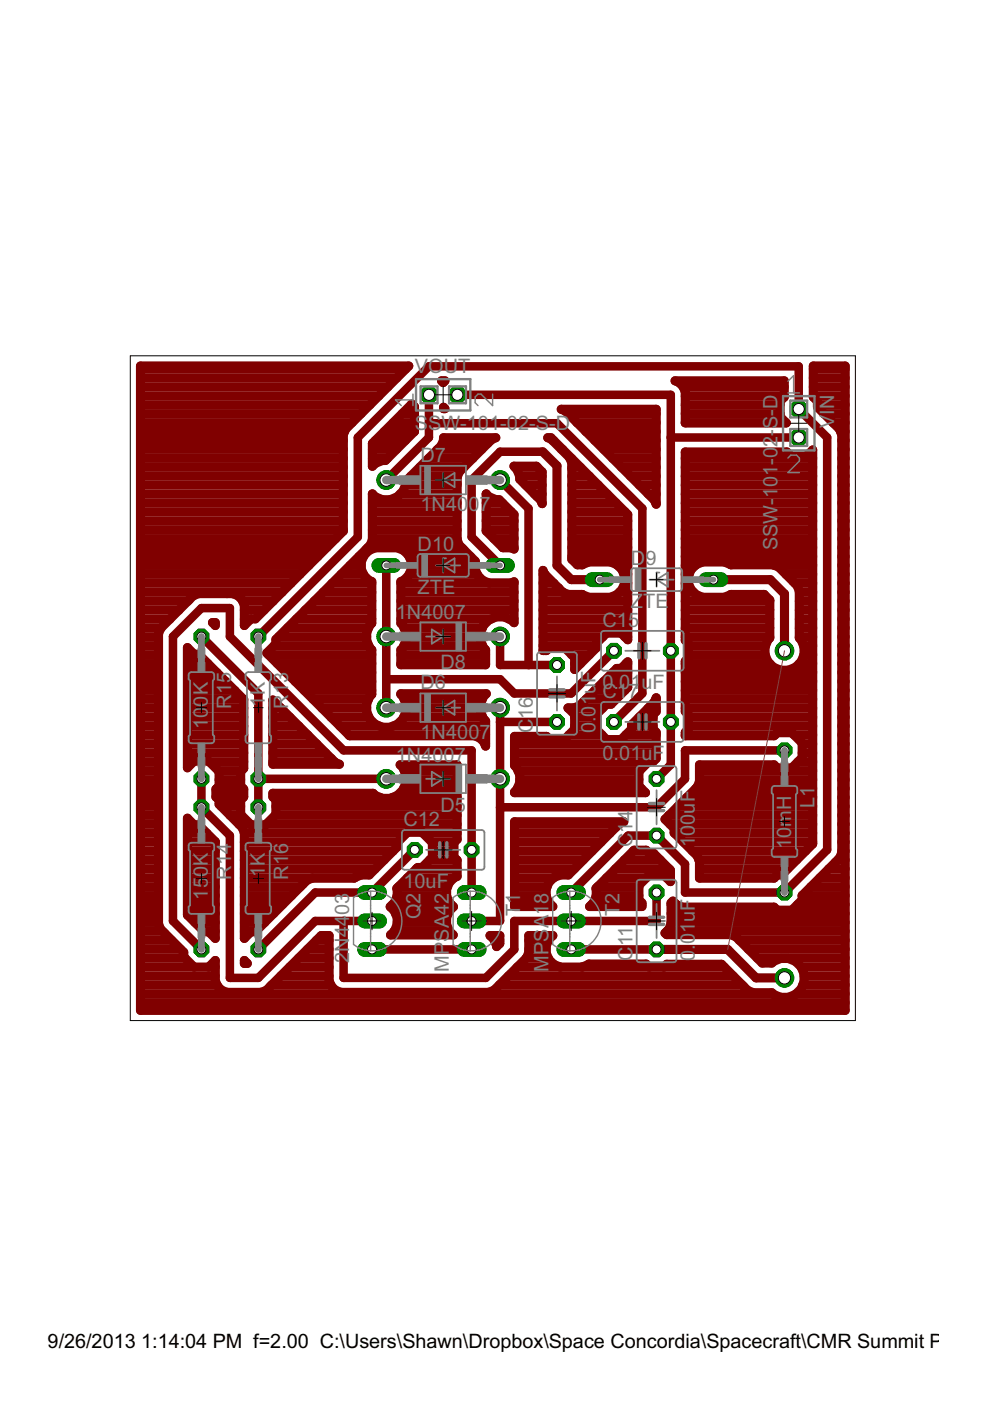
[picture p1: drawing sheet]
<svg xmlns="http://www.w3.org/2000/svg" width="176mm" height="250mm" viewBox="0 0 176 250" stroke-linecap="round" stroke-linejoin="round" font-family="sans-serif">
<defs><g id="words">
<g font-size="4" fill="#808080">
<text x="74" y="66.7">VOUT</text>
<text x="74" y="76.8">SSW-101-02-S-D</text>
<text x="138.8" y="77.8" transform="rotate(-90 138.8 77.8)">-S</text>
<text x="138.8" y="74.2" transform="rotate(-90 138.8 74.2)">-</text>
<text x="138.8" y="73.1" transform="rotate(-90 138.8 73.1)">D</text>
<text x="149" y="76.4" transform="rotate(-90 149 76.4)">VI</text>
<text x="149" y="73.1" transform="rotate(-90 149 73.1)">N</text>
<text x="75.1" y="82.4">D7</text>
<text x="138.8" y="83" transform="rotate(-90 138.8 83)">-</text>
<text x="138.8" y="81.8" transform="rotate(-90 138.8 81.8)">0</text>
<text x="138.8" y="79.8" transform="rotate(-90 138.8 79.8)">2</text>
<text x="138.8" y="89" transform="rotate(-90 138.8 89)">10</text>
<text x="138.8" y="85" transform="rotate(-90 138.8 85)">1</text>
<text x="75.1" y="91.3">1N4</text>
<text x="81.6" y="91.3">007</text>
<text x="138.8" y="95.9" transform="rotate(-90 138.8 95.9)">S</text>
<text x="138.8" y="93.5" transform="rotate(-90 138.8 93.5)">W-</text>
<text x="74.6" y="98.4">D10</text>
<text x="112.6" y="100.9">D</text>
<text x="115.2" y="100.9">9</text>
<text x="138.8" y="98.2" transform="rotate(-90 138.8 98.2)">S</text>
<text x="74.6" y="106">ZTE</text>
<text x="70.7" y="110.6">1</text>
<text x="72.6" y="110.6">N4007</text>
<text x="107.6" y="111.9">C1</text>
<text x="112.1" y="111.9">5</text>
<text x="112.6" y="108.6">Z</text>
<text x="114.8" y="108.6">TE</text>
<text x="78.6" y="119.5">D8</text>
<text x="37.1" y="124.2" transform="rotate(-90 37.1 124.2)">K</text>
<text x="41.3" y="124" transform="rotate(-90 41.3 124)">15</text>
<text x="75.1" y="123">D6</text>
<text x="106.3" y="125.9" transform="rotate(-90 106.3 125.9)">1</text>
<text x="106.3" y="123.9" transform="rotate(-90 106.3 123.9)">uF</text>
<text x="107.6" y="124.6">C17</text>
<text x="107.6" y="123">0.01uF</text>
<text x="37.1" y="130.1" transform="rotate(-90 37.1 130.1)">10</text>
<text x="37.1" y="126.2" transform="rotate(-90 37.1 126.2)">0</text>
<text x="41.3" y="126.6" transform="rotate(-90 41.3 126.6)">R</text>
<text x="47.3" y="126.2" transform="rotate(-90 47.3 126.2)">1K</text>
<text x="51.4" y="126.6" transform="rotate(-90 51.4 126.6)">R13</text>
<text x="75.1" y="131.9">1N4007</text>
<text x="95.1" y="130.9" transform="rotate(-90 95.1 130.9)">C</text>
<text x="95.1" y="128.3" transform="rotate(-90 95.1 128.3)">16</text>
<text x="106.3" y="130.9" transform="rotate(-90 106.3 130.9)">0</text>
<text x="106.3" y="128.9" transform="rotate(-90 106.3 128.9)">.</text>
<text x="106.3" y="127.9" transform="rotate(-90 106.3 127.9)">0</text>
<text x="70.7" y="136">1N4007</text>
<text x="107.6" y="135.7">0.01uF</text>
<text x="124.1" y="143.3" transform="rotate(-90 124.1 143.3)">F</text>
<text x="72" y="147.4">C12</text>
<text x="78.6" y="144.9">D5</text>
<text x="112.9" y="148.6" transform="rotate(-90 112.9 148.6)">14</text>
<text x="124.1" y="149.2" transform="rotate(-90 124.1 149.2)">00</text>
<text x="124.1" y="145.3" transform="rotate(-90 124.1 145.3)">u</text>
<text x="141.2" y="149.6" transform="rotate(-90 141.2 149.6)">0</text>
<text x="141.2" y="147.7" transform="rotate(-90 141.2 147.7)">m</text>
<text x="141.2" y="144.7" transform="rotate(-90 141.2 144.7)">H</text>
<text x="145.4" y="144.3" transform="rotate(-90 145.4 144.3)">L1</text>
<text x="37.1" y="154.6" transform="rotate(-90 37.1 154.6)">K</text>
<text x="47.3" y="154.6" transform="rotate(-90 47.3 154.6)">K</text>
<text x="51.4" y="154.4" transform="rotate(-90 51.4 154.4)">1</text>
<text x="51.4" y="152.5" transform="rotate(-90 51.4 152.5)">6</text>
<text x="112.9" y="151.2" transform="rotate(-90 112.9 151.2)">C</text>
<text x="124.1" y="151.2" transform="rotate(-90 124.1 151.2)">1</text>
<text x="141.2" y="151.6" transform="rotate(-90 141.2 151.6)">1</text>
<text x="37.1" y="160.6" transform="rotate(-90 37.1 160.6)">15</text>
<text x="37.1" y="156.6" transform="rotate(-90 37.1 156.6)">0</text>
<text x="41.3" y="157" transform="rotate(-90 41.3 157)">R14</text>
<text x="47.3" y="156.6" transform="rotate(-90 47.3 156.6)">1</text>
<text x="51.4" y="157" transform="rotate(-90 51.4 157)">R</text>
<text x="72" y="158.6">10uF</text>
<text x="75.1" y="161.3" transform="rotate(-90 75.1 161.3)">2</text>
<text x="80.1" y="161.3" transform="rotate(-90 80.1 161.3)">2</text>
<text x="92.8" y="161.3" transform="rotate(-90 92.8 161.3)">1</text>
<text x="97.9" y="161.3" transform="rotate(-90 97.9 161.3)">8</text>
<text x="110.6" y="161.3" transform="rotate(-90 110.6 161.3)">2</text>
<text x="62.4" y="163.3" transform="rotate(-90 62.4 163.3)">03</text>
<text x="75.1" y="164.1" transform="rotate(-90 75.1 164.1)">Q</text>
<text x="80.1" y="165.7" transform="rotate(-90 80.1 165.7)">A4</text>
<text x="92.8" y="163.5" transform="rotate(-90 92.8 163.5)">T</text>
<text x="97.9" y="163.3" transform="rotate(-90 97.9 163.3)">1</text>
<text x="110.6" y="163.5" transform="rotate(-90 110.6 163.5)">T</text>
<text x="124.1" y="166.6" transform="rotate(-90 124.1 166.6)">1</text>
<text x="124.1" y="164.6" transform="rotate(-90 124.1 164.6)">u</text>
<text x="124.1" y="162.6" transform="rotate(-90 124.1 162.6)">F</text>
<text x="62.4" y="171.9" transform="rotate(-90 62.4 171.9)">2N44</text>
<text x="80.1" y="173.5" transform="rotate(-90 80.1 173.5)">MPS</text>
<text x="97.9" y="173.5" transform="rotate(-90 97.9 173.5)">MPSA</text>
<text x="112.9" y="171.5" transform="rotate(-90 112.9 171.5)">C</text>
<text x="112.9" y="169" transform="rotate(-90 112.9 169)">11</text>
<text x="124.1" y="171.5" transform="rotate(-90 124.1 171.5)">0.</text>
<text x="124.1" y="168.6" transform="rotate(-90 124.1 168.6)">0</text>
</g>
<g font-size="4">
<text x="8.5" y="240.6">9/26/2013</text>
<text x="25.2" y="240.6">1:14:04 PM f=2.00 C:\Users\Shawn\Dropbox\Space Concordia\Spacecraft\CMR Summit PCB M</text>
</g>
</g></defs>
<circle cx="46.1" cy="113.6" r="1.42" fill="#008000" stroke="#008000" stroke-width=".18"/>
<circle cx="46.1" cy="113.6" r=".8" fill="#fff" stroke="#000" stroke-width=".18"/>
<circle cx="46.1" cy="139" r="1.42" fill="#008000" stroke="#008000" stroke-width=".18"/>
<circle cx="46.1" cy="139" r=".8" fill="#fff" stroke="#000" stroke-width=".18"/>
<circle cx="36" cy="144.1" r="1.42" fill="#008000" stroke="#008000" stroke-width=".18"/>
<circle cx="36" cy="144.1" r=".8" fill="#fff" stroke="#000" stroke-width=".18"/>
<circle cx="36" cy="169.5" r="1.42" fill="#008000" stroke="#008000" stroke-width=".18"/>
<circle cx="36" cy="169.5" r=".8" fill="#fff" stroke="#000" stroke-width=".18"/>
<circle cx="36" cy="113.6" r="1.42" fill="#008000" stroke="#008000" stroke-width=".18"/>
<circle cx="36" cy="113.6" r=".8" fill="#fff" stroke="#000" stroke-width=".18"/>
<circle cx="36" cy="139" r="1.42" fill="#008000" stroke="#008000" stroke-width=".18"/>
<circle cx="36" cy="139" r=".8" fill="#fff" stroke="#000" stroke-width=".18"/>
<circle cx="46.1" cy="144.1" r="1.42" fill="#008000" stroke="#008000" stroke-width=".18"/>
<circle cx="46.1" cy="144.1" r=".8" fill="#fff" stroke="#000" stroke-width=".18"/>
<circle cx="46.1" cy="169.5" r="1.42" fill="#008000" stroke="#008000" stroke-width=".18"/>
<circle cx="46.1" cy="169.5" r=".8" fill="#fff" stroke="#000" stroke-width=".18"/>
<circle cx="117.2" cy="169.5" r="1.42" fill="#008000" stroke="#008000" stroke-width=".18"/>
<circle cx="117.2" cy="169.5" r=".8" fill="#fff" stroke="#000" stroke-width=".18"/>
<circle cx="117.2" cy="159.3" r="1.42" fill="#008000" stroke="#008000" stroke-width=".18"/>
<circle cx="117.2" cy="159.3" r=".8" fill="#fff" stroke="#000" stroke-width=".18"/>
<circle cx="74" cy="151.7" r="1.42" fill="#008000" stroke="#008000" stroke-width=".18"/>
<circle cx="74" cy="151.7" r=".8" fill="#fff" stroke="#000" stroke-width=".18"/>
<circle cx="84.2" cy="151.7" r="1.42" fill="#008000" stroke="#008000" stroke-width=".18"/>
<circle cx="84.2" cy="151.7" r=".8" fill="#fff" stroke="#000" stroke-width=".18"/>
<circle cx="117.2" cy="149.2" r="1.42" fill="#008000" stroke="#008000" stroke-width=".18"/>
<circle cx="117.2" cy="149.2" r=".8" fill="#fff" stroke="#000" stroke-width=".18"/>
<circle cx="117.2" cy="139" r="1.42" fill="#008000" stroke="#008000" stroke-width=".18"/>
<circle cx="117.2" cy="139" r=".8" fill="#fff" stroke="#000" stroke-width=".18"/>
<circle cx="109.6" cy="116.2" r="1.42" fill="#008000" stroke="#008000" stroke-width=".18"/>
<circle cx="109.6" cy="116.2" r=".8" fill="#fff" stroke="#000" stroke-width=".18"/>
<circle cx="119.8" cy="116.2" r="1.42" fill="#008000" stroke="#008000" stroke-width=".18"/>
<circle cx="119.8" cy="116.2" r=".8" fill="#fff" stroke="#000" stroke-width=".18"/>
<circle cx="99.4" cy="128.9" r="1.42" fill="#008000" stroke="#008000" stroke-width=".18"/>
<circle cx="99.4" cy="128.9" r=".8" fill="#fff" stroke="#000" stroke-width=".18"/>
<circle cx="99.4" cy="118.7" r="1.42" fill="#008000" stroke="#008000" stroke-width=".18"/>
<circle cx="99.4" cy="118.7" r=".8" fill="#fff" stroke="#000" stroke-width=".18"/>
<circle cx="109.6" cy="128.9" r="1.42" fill="#008000" stroke="#008000" stroke-width=".18"/>
<circle cx="109.6" cy="128.9" r=".8" fill="#fff" stroke="#000" stroke-width=".18"/>
<circle cx="119.8" cy="128.9" r="1.42" fill="#008000" stroke="#008000" stroke-width=".18"/>
<circle cx="119.8" cy="128.9" r=".8" fill="#fff" stroke="#000" stroke-width=".18"/>
<path d="M65.1 169.5h2.7" fill="none" stroke="#008000" stroke-width="2.6"/>
<circle cx="66.4" cy="169.5" r=".8" fill="#fff" stroke="#000" stroke-width=".18"/>
<path d="M65.1 159.3h2.7" fill="none" stroke="#008000" stroke-width="2.6"/>
<circle cx="66.4" cy="159.3" r=".8" fill="#fff" stroke="#000" stroke-width=".18"/>
<path d="M65.1 164.4h2.7" fill="none" stroke="#008000" stroke-width="2.6"/>
<circle cx="66.4" cy="164.4" r=".8" fill="#fff" stroke="#000" stroke-width=".18"/>
<circle cx="69" cy="139" r="1.67" fill="#008000" stroke="#008000" stroke-width=".18"/>
<circle cx="69" cy="139" r="1.12" fill="#fff" stroke="#000" stroke-width=".18"/>
<circle cx="89.3" cy="139" r="1.67" fill="#008000" stroke="#008000" stroke-width=".18"/>
<circle cx="89.3" cy="139" r="1.12" fill="#fff" stroke="#000" stroke-width=".18"/>
<circle cx="89.3" cy="126.3" r="1.67" fill="#008000" stroke="#008000" stroke-width=".18"/>
<circle cx="89.3" cy="126.3" r="1.12" fill="#fff" stroke="#000" stroke-width=".18"/>
<circle cx="69" cy="126.3" r="1.67" fill="#008000" stroke="#008000" stroke-width=".18"/>
<circle cx="69" cy="126.3" r="1.12" fill="#fff" stroke="#000" stroke-width=".18"/>
<circle cx="89.3" cy="85.7" r="1.67" fill="#008000" stroke="#008000" stroke-width=".18"/>
<circle cx="89.3" cy="85.7" r="1.12" fill="#fff" stroke="#000" stroke-width=".18"/>
<circle cx="69" cy="85.7" r="1.67" fill="#008000" stroke="#008000" stroke-width=".18"/>
<circle cx="69" cy="85.7" r="1.12" fill="#fff" stroke="#000" stroke-width=".18"/>
<circle cx="140.1" cy="134" r="1.42" fill="#008000" stroke="#008000" stroke-width=".18"/>
<circle cx="140.1" cy="134" r=".8" fill="#fff" stroke="#000" stroke-width=".18"/>
<circle cx="140.1" cy="159.3" r="1.42" fill="#008000" stroke="#008000" stroke-width=".18"/>
<circle cx="140.1" cy="159.3" r=".8" fill="#fff" stroke="#000" stroke-width=".18"/>
<circle cx="69" cy="113.6" r="1.67" fill="#008000" stroke="#008000" stroke-width=".18"/>
<circle cx="69" cy="113.6" r="1.12" fill="#fff" stroke="#000" stroke-width=".18"/>
<circle cx="89.3" cy="113.6" r="1.67" fill="#008000" stroke="#008000" stroke-width=".18"/>
<circle cx="89.3" cy="113.6" r="1.12" fill="#fff" stroke="#000" stroke-width=".18"/>
<path d="M82.9 164.4h2.6" fill="none" stroke="#008000" stroke-width="2.6"/>
<circle cx="84.2" cy="164.4" r=".8" fill="#fff" stroke="#000" stroke-width=".18"/>
<path d="M82.9 159.3h2.6" fill="none" stroke="#008000" stroke-width="2.6"/>
<circle cx="84.2" cy="159.3" r=".8" fill="#fff" stroke="#000" stroke-width=".18"/>
<path d="M82.9 169.5h2.6" fill="none" stroke="#008000" stroke-width="2.6"/>
<circle cx="84.2" cy="169.5" r=".8" fill="#fff" stroke="#000" stroke-width=".18"/>
<path d="M100.7 164.4h2.6" fill="none" stroke="#008000" stroke-width="2.6"/>
<circle cx="102" cy="164.4" r=".8" fill="#fff" stroke="#000" stroke-width=".18"/>
<path d="M100.7 159.3h2.6" fill="none" stroke="#008000" stroke-width="2.6"/>
<circle cx="102" cy="159.3" r=".8" fill="#fff" stroke="#000" stroke-width=".18"/>
<path d="M100.7 169.5h2.6" fill="none" stroke="#008000" stroke-width="2.6"/>
<circle cx="102" cy="169.5" r=".8" fill="#fff" stroke="#000" stroke-width=".18"/>
<path d="M105.7 103.5h2.7" fill="none" stroke="#008000" stroke-width="2.6"/>
<circle cx="107.1" cy="103.5" r=".8" fill="#fff" stroke="#000" stroke-width=".18"/>
<path d="M126 103.5h2.7" fill="none" stroke="#008000" stroke-width="2.6"/>
<circle cx="127.4" cy="103.5" r=".8" fill="#fff" stroke="#000" stroke-width=".18"/>
<path d="M67.6 100.9h2.7" fill="none" stroke="#008000" stroke-width="2.6"/>
<circle cx="69" cy="100.9" r=".8" fill="#fff" stroke="#000" stroke-width=".18"/>
<path d="M88 100.9h2.6" fill="none" stroke="#008000" stroke-width="2.6"/>
<circle cx="89.3" cy="100.9" r=".8" fill="#fff" stroke="#000" stroke-width=".18"/>
<circle cx="76.6" cy="70.5" r="1.62" fill="#008000" stroke="#008000" stroke-width=".18"/>
<circle cx="76.6" cy="70.5" r=".99" fill="#fff" stroke="#000" stroke-width=".18"/>
<circle cx="81.7" cy="70.5" r="1.62" fill="#008000" stroke="#008000" stroke-width=".18"/>
<circle cx="81.7" cy="70.5" r=".99" fill="#fff" stroke="#000" stroke-width=".18"/>
<circle cx="142.6" cy="73" r="1.62" fill="#008000" stroke="#008000" stroke-width=".18"/>
<circle cx="142.6" cy="73" r=".99" fill="#fff" stroke="#000" stroke-width=".18"/>
<circle cx="142.6" cy="78.1" r="1.62" fill="#008000" stroke="#008000" stroke-width=".18"/>
<circle cx="142.6" cy="78.1" r=".99" fill="#fff" stroke="#000" stroke-width=".18"/>
<circle cx="140.1" cy="116.2" r="1.65" fill="#008000" stroke="#008000" stroke-width=".18"/>
<circle cx="140.1" cy="116.2" r="1.1" fill="#fff" stroke="#000" stroke-width=".18"/>
<circle cx="140.1" cy="174.6" r="1.65" fill="#008000" stroke="#008000" stroke-width=".18"/>
<circle cx="140.1" cy="174.6" r="1.1" fill="#fff" stroke="#000" stroke-width=".18"/>
<g fill="none" stroke="#800000" stroke-width="1.5">
<path d="M76.6 75.6h22.8l15.3 15.2v33l-5.1 5.1M76.6 70.5v7.6l-7.6 7.6M81.7 70.5h38.1v66l-2.6 2.5M119.8 78.1h22.8M89.3 85.7l5.1 5.1v27.9M96.9 80.6h-7.6l-5.1 5.1v10.2l5.1 5M36 113.6l10.1 10.2v20.3M46.1 113.6l17.8-17.7v-17.8l12.7-12.7h66v7.6l5.1 5.1v73.6l-7.6 7.6h-17.8v-5l-5.1-5.1h-5.1l-10.1 10.1M69 100.9v25.4M89.3 113.6v5.1h10.1M109.6 116.2l-7.6 7.6h-10.2l-2.5-2.5h-20.3M36 139v5.1l5 5.1v25.4h5.1l10.2-10.2h10.1"/>
<path d="M46.1 139h22.9M89.3 126.3v38.1h-5.1M89.3 128.9h10.1M140.1 134h-17.8v5l-5.1 5.1h-27.9M74 151.7l-7.6 7.6h-10.1l-10.2 10.2M84.2 159.3v-25.3h-22.9l-20.3-20.4v-5h-5l-5.1 5v50.8l5.1 5.1M117.2 159.3v5.1h-25.4v5.1l-5.1 5.1h-25.4v-10.2M66.4 169.5h17.8M102 169.5h15.2"/>
</g>
<g fill="none" stroke="#800000" stroke-width="1.6">
<path d="M25.1 78.6h36.2M25.1 77h36.4M25.1 75.5h37.8M25.1 73.9h39.4M25.1 72.3h41M25.1 70.7h42.5M25.1 69.1h44.2M25.1 67.5h45.7M25.1 65.9h47.3M66.5 79.2l7-7.1 .5 .5v4.4l-5.2 5.2h-.5l-1.3 .5-.5 .5zM67 78.6h5.4M68.6 77h5.4"/>
<path d="M70.2 75.5h3.8M71.8 73.9h2.2M73.4 72.3h.3M78.8 68h.6l-.3 .3zM79.2 78.6h8.4M79.2 72.7l.2 .3h-.2zM98.6 78.6h.2M100.2 73.1h17v16.9l-.3-.7-15.3-15.2-.7-.7zM101.4 73.9h15.8M103 75.5h14.2M104.6 77h12.6M106.2 78.6h11"/>
<path d="M120.5 68h19.5v2.9l-.7 .7v2.8l1.1 1.1h-18.1v-5.5l-.4-1-.7-.7zM122 69.1h18M122.3 75.5h18M122.3 73.9h17M122.3 72.3h17M122.3 70.7h17.7M145.2 70.7h5.7M145.2 69.1h5.7M145.2 67.5h5.7M145.2 65.9h5.7M145.9 72.3h5M147.1 73.9h3.8"/>
<path d="M148.7 75.5h2.2M150.1 77h.8M150.3 78.6h.6M25.1 99.4h31.6M25.1 97.7h33.2M25.1 96.2h34.8M25.1 94.6h36.2M25.1 93h36.2M25.1 91.4h36.2M25.1 89.8h36.2M25.1 88.2h36.2M25.1 86.6h36.2"/>
<path d="M25.1 85h36.2M25.1 83.4h36.2M25.1 81.8h36.2M25.1 80.2h36.2M64.1 99.4h.8M65.7 97.7h16.7M66.5 88.2a3.5 3.5 0 0 0 3.8 .8 3.5 3.5 0 0 0 2.2-3.1l6.3-6.3 .4-1v-.5h9.3l-.7 .3-5.8 5.8-.4 1v11.2l.4 .9 2.9 2.9a3.2 3.2 0 0 0 2.4 3.9h3.9l.6-.2v7.3a3.5 3.5 0 0 0-5-.1 3.5 3.5 0 0 0-.1 4.9v2.7h-15.1v-2.7a3.3 3.3 0 0 0 0-4.7v-7.5a3.2 3.2 0 0 0 1.9-3.2 3.2 3.2 0 0 0-2.6-2.8h-3.9a3.2 3.2 0 0 0-2.5 2.8 3.2 3.2 0 0 0 1.9 3.2v7.5a3.3 3.3 0 0 0 0 4.7v8a3.6 3.6 0 0 0 .2 4.9 3.6 3.6 0 0 0 5-.1 3.6 3.6 0 0 0 0-5h15.2a3.4 3.4 0 0 0-.1 4.9v4.5l-.3-.7-.7-.7-1-.4h-22.3l-14.8-14.8 1.7-1.6v-.8l16.8-16.9 .4-.9zM66.5 96.2h15.1M66.5 94.6h15.1M66.5 93h15.1M66.5 91.4h15.1M66.5 89.8h15.1"/>
<path d="M66.5 88.2h.1M66.5 81.8h2.7M66.5 80.2h4.3M71.4 88.2h10.2M72.4 86.6h9.2M73 99.4h11M73.3 85h8.4M74.9 83.4h7.9M76.5 81.8h7.9M78.1 80.2h7.9M86.8 88.2l.5 .5 1.3 .5h.5l2.7 2.7v6.1l-.6-.2h-1.4l-3-3zM86.8 94.6h5"/>
<path d="M86.8 93h5M86.8 91.4h4.5M86.8 89.8h2.9M86.8 88.2h.1M88.2 96.2h3.6M89.7 97.7h2.1M91.8 83.2h4l1 1.1v5.6l-.2-.6-3.8-3.7v-.6l-.6-1.3zM91.9 83.4h4M92.8 85h4M93.8 86.6h3M95.4 88.2h1.4M96.8 89.8h.1"/>
<path d="M96.9 80.6l2.5 2.6v17.7l2.6 2.6h5.1M100.2 80.2h.3M101.7 81.8h.3M102.1 99.4h10M102.1 97.7h10M102.1 96.2h10M102.1 94.6h10M102.1 93h10M102.1 91.4h9.5M102.1 89.8h7.9M102.1 88.2h6.3M102.1 86.6h4.7"/>
<path d="M102.1 85h3.1M102.1 83.4h1.5M107.8 80.2h9.4M109.4 81.8h7.8M111 83.4h6.2M112.6 85h4.6M114.2 86.6h3M115.7 88.2h1.5M117.1 89.8h.1M122.3 80.7h18.2l.7 .7h2.8l1.1-1.1v70.4l-5.5 5.5h-.8l-.6 .6h-13.3v-3l-.4-1-4.1-4.1v-.8l-1.7-1.6 5.8-5.8 .4-.9v-3.1h13.3l.6 .6h2.6l1.8-1.8v-2.6l-1.8-1.9h-2.6l-.6 .6h-15.9v-.7l.6-.5v-2.6l-.6-.6v-9l.6-.5v-2.6l-.6-.6zM122.3 99.4h22.8M122.3 97.7h22.8"/>
<path d="M122.3 96.2h22.8M122.3 94.6h22.8M122.3 93h22.8M122.3 91.4h22.8M122.3 89.8h22.8M122.3 88.2h22.8M122.3 86.6h22.8M122.3 85h22.8M122.3 83.4h22.8M122.3 81.8h22.8M150.3 99.4h.6M150.3 97.7h.6"/>
<path d="M150.3 96.2h.6M150.3 94.6h.6M150.3 93h.6M150.3 91.4h.6M150.3 89.8h.6M150.3 88.2h.6M150.3 86.6h.6M150.3 85h.6M150.3 83.4h.6M150.3 81.8h.6M150.3 80.2h.6M25.1 118.5h3.2"/>
<path d="M25.1 116.9h3.2M25.1 115.3h3.2M25.1 113.7h3.2M25.1 112.1h3.7M25.1 110.5h5.3M25.1 108.9h6.9M25.1 107.3h8.4M25.1 105.7h25.3M25.1 104.1h26.9M25.1 102.5h28.5M25.1 100.9h30.1M33.5 115.6l1.1 1.2h.9l8 8.1v12.3l-.5 .5v2.6l.5 .6v1.4l-.5 .5v2.6l1.8 1.9h2.6l1.9-1.9v-2.6l-.6-.5v-.7h17.9a3.5 3.5 0 0 0 5-.1 3.5 3.5 0 0 0-.2-5h10.2v13.4l-.6 .5v2.6l.6 .6v2.9a3.1 3.1 0 0 0-.6 5.4 3.1 3.1 0 0 0-.1 5h-11.2a3.1 3.1 0 0 0 0-5 2.98 2.98 0 0 0 1.1-3.3l3.8-3.7h.8l1.8-1.9v-2.6l-1.8-1.8h-2.7l-1.8 1.8v.8l-5 5h-1.4l-1.3 .6h-7.4l-1 .4-9.2 9.1h-.8l-1.2 1.2v-18.8l-.4-1-4.1-4.1v-.8l-.6-.5v-1.4l.6-.6v-2.6l-1.8-1.8h-2.7l-1.1 1.2z"/>
<path d="M33.5 118.5h3.6M33.5 116.9h2M37.9 111.1h.5v.6zM43.3 107.3h5.5M43.6 110.5h1.2M43.6 108.9h3.6M47.9 116.9h18.5M48.9 115.3h16.9M49.5 118.5h16.9M49.7 113.7h15.8M51.3 112.1h14.5M52.9 110.5h13.5"/>
<path d="M54.5 108.9h11.9M56.1 107.3h10.3M57.7 105.7h8.7M59.3 104.1h7.1M60.9 102.5h4M62.5 100.9h2M71.6 118.5h15.1M71.6 116.9h15.1M71.6 110.5h16.1M71.6 108.9h20.2M71.6 107.3h20.2M71.6 105.7h20.2"/>
<path d="M71.6 104.1h20.2M72.1 115.3h14.1M72.1 112.1h14M72.5 113.7h13.3M73 102.5h12.2M73.4 100.9h11.4M90.8 110.5h1M96.9 115.3h9.5M96.9 113.7h10.7M96.9 112.1h15.2M96.9 110.5h15.2M96.9 108.9h15.2"/>
<path d="M96.9 107.3h15.2M96.9 105.7h3.6M96.9 104.1h2M96.9 102.5h.4M99.7 105h.1M102 116.9h3.2M102.6 118.5h1.1M110.3 100.9h1.8M110.6 105.7h1.5M111.4 102.5h.7M111.5 104.1a3.2 3.2 0 0 0-2.5-3.8h-3.9l-1.2 .5h-.8l-1-.9v-17.2l-.4-1-3.3-3.3-.6-.3h.6l13.7 13.8v22.3l-1.2-1.2h-2.6l-1.9 1.9v.8l-3.8 3.8v-2.1l-1.8-1.8h-2.7l-.5 .5h-.7v-14.3l.3 .6 3.3 3.3M111.5 104.1l-.5 1.2-.8 .9-1.2 .4h-3.9l-1.2-.5h-2.4l-1-.4"/>
<path d="M111.5 104.1h.6M111.5 113.7h.6M111.8 118.5h.3M122.3 118.5h15.1M122.3 113.7h15.1M122.3 112.1h15.1M122.3 110.5h15.1M122.3 108.9h15.1M122.3 107.3h15.1M122.3 105.7h1.5M122.3 104.1h.6M122.3 102.5h.7"/>
<path d="M122.3 100.9h1.8M122.9 116.9h13.7M122.9 115.3h13.8M127.4 103.5h10.1l2.6 2.5v10.2M136.6 116.9v-1.4l.5-1.3 .3-.3v-6.8l-1-1h-5.9l-1.2 .5h-3.9a3.2 3.2 0 0 1-2.6-3.1 3.2 3.2 0 0 1 2.6-3.2h3.9l1.2 .5h7.5l1 .4 3.3 3.3 .4 1v8.4l.3 .3 .6 1.3v1.4M136.6 116.9a3.6 3.6 0 0 0 3.5 2.8 3.6 3.6 0 0 0 3.5-2.8M138.3 100.9h6.8M140.3 102.5h4.8M141.9 104.1h3.2M142.7 118.5h2.4M142.7 113.7h2.4M142.7 112.1h2.4"/>
<path d="M142.7 110.5h2.4M142.7 108.9h2.4M142.7 107.3h2.4M142.7 105.7h2.4M143.5 115.3h1.6M143.6 116.9h1.5M150.3 118.5h.6M150.3 116.9h.6M150.3 115.3h.6M150.3 113.7h.6M150.3 112.1h.6M150.3 110.5h.6"/>
<path d="M150.3 108.9h.6M150.3 107.3h.6M150.3 105.7h.6M150.3 104.1h.6M150.3 102.5h.6M150.3 100.9h.6M25.1 139.2h3.2M25.1 137.6h3.2M25.1 136h3.2M25.1 134.4h3.2M25.1 132.8h3.2M25.1 131.2h3.2"/>
<path d="M25.1 129.6h3.2M25.1 128h3.2M25.1 126.4h3.2M25.1 124.8h3.2M25.1 123.3h3.2M25.1 121.7h3.2M25.1 120.1h3.2M33.5 136h1M33.5 134.4h10M33.5 132.8h10M33.5 131.2h10M33.5 129.6h10"/>
<path d="M33.5 128h10M33.5 126.4h10M33.5 124.8h10M33.5 123.3h8.4M33.5 121.7h6.8M33.5 120.1h5.2M37.4 136h6.1M39 137.6h4.1M39.1 139.2h3.9M48.7 125l11.2 11.1 .7 .3h-11.9zM48.7 136h11M48.7 134.4h9.4"/>
<path d="M48.7 132.8h7.8M48.7 131.2h6.2M48.7 129.6h4.7M48.7 128h3.1M48.7 126.4h1.5M51.1 120.1h15.3M52.7 121.7h13.7M54.3 123.3h12.1M55.9 124.8h9.9M57.5 126.4h8M59.1 128h6.8M60.7 129.6h7"/>
<path d="M62.3 131.2h24.4M70.2 129.6h16.5M72.1 128h14.1M72.1 124.8h14M72.2 137.6h9.4M72.5 139.2h9.1M72.5 126.4h13.3M86.5 132.8h.2M91.9 131.5h5.7l.5 .5h2.7l1.8-1.8v-2.6l-1.2-1.2h1.1l.9-.4 6.7-6.7h.8l1.2-1.1v4.5l-3 3h-.8l-1.9 1.9v2.6l1.9 1.8h2.6l1.9-1.8v-.8l4.1-4.1 .3-.7v2.4l-.6 .6v2.6l.6 .5v4.7l-.5 .5h-.8l-1.8 1.8v2.6l1.2 1.2h-23.4a3.5 3.5 0 0 0 0-4.8zM91.9 136h23.9M91.9 134.4h25.3M91.9 132.8h25.3"/>
<path d="M92.5 137.6h21.7M92.8 139.2h21.3M101.5 126.4h6.1M101.6 131.2h5.9M102.6 129.6h3.8M102.6 128h3.8M104.6 124.8h5.4M106.2 123.3h5.4M107.8 121.7h4.3M109.4 120.1h2.7M111.7 131.2h5.5M112.8 129.6h3.8"/>
<path d="M114.1 128h2.5M115.7 126.4h1.5M117.1 124.8h.1M122.3 131.2h16.1M122.3 126.4h22.8M122.3 124.8h22.8M122.3 123.3h22.8M122.3 121.7h22.8M122.3 120.1h22.8M122.9 129.6h22.2M122.9 128h22.2M124.9 139.2h20.2"/>
<path d="M124.9 137.6h20.2M141.8 131.2h3.3M142.5 136h2.6M143.2 134.4h1.9M143.2 132.8h1.9M150.3 139.2h.6M150.3 137.6h.6M150.3 136h.6M150.3 134.4h.6M150.3 132.8h.6M150.3 131.2h.6M150.3 129.6h.6"/>
<path d="M150.3 128h.6M150.3 126.4h.6M150.3 124.8h.6M150.3 123.3h.6M150.3 121.7h.6M150.3 120.1h.6M25.1 159.9h3.2M25.1 158.3h3.2M25.1 156.7h3.2M25.1 155.1h3.2M25.1 153.5h3.2M25.1 151.9h3.2"/>
<path d="M25.1 150.3h3.2M25.1 148.7h3.2M25.1 147.2h3.2M25.1 145.6h3.2M25.1 144h3.2M25.1 142.4h3.2M25.1 140.8h3.2M33.5 146.1l1.1 1.2h.9l2.9 3v17.2l-1.1-1.2h-.8l-3-2.9zM33.5 159.9h4.9M33.5 158.3h4.9M33.5 156.7h4.9M33.5 155.1h4.9"/>
<path d="M33.5 153.5h4.9M33.5 151.9h4.9M33.5 150.3h4.9M33.5 148.7h3.4M33.5 147.2h1M38.7 142.4h4.7M38.7 140.8h4.7M39.5 144h3.5M41.1 145.6h2M42.7 147.2h2M43.6 159.9h8.5M43.6 158.3h10.1"/>
<path d="M43.6 156.7h19.7M43.6 155.1h23.4M43.6 153.5h25M43.6 151.9h26.6M43.6 150.3h27.4M43.6 148.7h29M47.5 147.2h34.1M48.8 142.4h19.1M49.1 145.6h32.5M49.3 144h32.3M70.1 142.4h11.5M70.9 159.9h8.8"/>
<path d="M71.1 158.3h8.8M72.1 140.8h9.5M72.7 156.7h8.4M74.3 155.1h7.3M75.5 148.7h6.1M76.7 153.5h4.8M77.1 150.3h4.1M77.2 151.9h3.8M91.9 146.7h19.5l-.7 .3-9.2 9.2a3.2 3.2 0 0 0-3.7 1.7 3.2 3.2 0 0 0 .9 3.9h-6.8zM91.9 159.9h5.6M91.9 158.3h5.8M91.9 156.7h6.9"/>
<path d="M91.9 155.1h10.7M91.9 153.5h12.2M91.9 151.9h13.8M91.9 150.3h15.4M91.9 148.7h17M91.9 147.2h18.6M92.4 140.8h22.1M106.4 159.9h7.7M106.7 158.3h7.4M108.3 156.7h7.1M109.9 155.1h9.6M111.5 153.5h6.4"/>
<path d="M113.1 151.9h2.4M113.2 151.8h2.2l.5 .5h.8l3 3v2.1l-1.2-1.2h-2.6l-1.8 1.9v2.6l.5 .5v.6h-9.3a3.1 3.1 0 0 0 1.1-3.2zM119 156.7h.7M119.4 145.6h25.7M119.6 147.2h25.5M120.4 148.7h24.7M121 144h24.1M122 150.3h23.1M122.6 142.4h22.5M123.6 151.9h20.2M124.2 140.8h20.9M124.8 153.5h17.4"/>
<path d="M124.9 156.7h13.4M124.9 155.1h15.7M143.2 159.9l6.7-6.7 .4-.9v-74.7l-.4-1-4-3.9v-1.1l-.7-.7v-5.6h5.7v115.1h-125.8v-115.1h47.9l-11.3 11.3-.4 1v17.2l-15.7 15.7h-.8l-1.2 1.2v-3.6l-.4-1-.7-.7-.9-.4h-6.2l-.9 .4-5.8 5.8-.4 .9v51.9l.4 .9 4.1 4.1v.8l1.8 1.9M143.2 159.9v.8l-1.8 1.8h-2.6l-.6-.6h-16.4l-1-.4-.7-.6-.3 .3v3.8l-.4 .9-.7 .7 .3 .3h11.4l1 .4 4.7 4.6h1.7a3.5 3.5 0 0 1 4.8 .3 3.5 3.5 0 0 1 0 4.8 3.5 3.5 0 0 1-4.8 .2h-3.3l-1-.4-4.7-4.7h-9.8l-.5 .6M143.2 159.9h7.7M144.8 158.3h6.1M146.4 156.7h4.5M148 155.1h2.9M149.6 153.5h1.3M150.3 151.9h.6M150.3 150.3h.6M150.3 148.7h.6"/>
<path d="M150.3 147.2h.6M150.3 145.6h.6M150.3 144h.6M150.3 142.4h.6M150.3 140.8h.6M25.1 172.6h13.3M25.1 179h125.8M25.1 177.4h112.9M25.1 175.8h13.7M25.1 174.2h13.3M25.1 171h7.9M25.1 169.5h7.1"/>
<path d="M25.1 167.9h5.5M25.1 166.3h4M25.1 164.7h3.2M25.1 163.1h3.2M25.1 161.5h3.2M33.5 163.1h4.9M33.5 161.5h4.9M34.8 164.7h3.6M36.4 166.3h2M37.3 172.7l1.1-1.2v3.6l.4 .9 .8 .8 .9 .4h6.1l1-.4 9.7-9.8h1.5v8.1l.4 .9 .7 .8 .9 .4h26.4l1-.4 5.8-5.8 .4-1v-3h4.3a3.2 3.2 0 0 0-1.2 3.3 3.2 3.2 0 0 0 2.5 2.4M43.6 171.5l.6 .5h-.6zM43.6 166.3h2.1"/>
<path d="M43.6 164.7h3.7M43.6 163.1h5.3M43.6 161.5h6.9M48.5 175.8h10.6M50.1 174.2h8.7M51.7 172.6h7.1M53.3 171h5.5M54.9 169.5h3.9M56.5 167.9h2.3M70.1 161.5h10.5M70.4 166.3h9.9M70.6 163.1h9.4"/>
<path d="M70.9 164.7h8.8M87.5 167h1.7v1.4l-.5 .6-.5-1.3zM88.2 167.9h1M89.2 175.8h43.3M90.8 174.2h40.1M91.9 161.5h6.4M92.4 172.6h36.9M93.9 171h4M94.4 169.5h3.1M94.4 167.9h3.5M103.9 172.7l1.3-.6h10.2l.5 .6M105.6 161.5h9"/>
<path d="M117.2 169.5h12.7l5.1 5.1h5.1M119 166.3h31.9M119.8 164.7h31.1M119.8 163.1h31.1M119.8 161.5h1M132 167.9h18.9M133.6 169.5h17.3M135.2 171h15.7M142.2 177.4h8.7M142.4 161.5h8.5M143 172.6h7.9M143.3 175.8h7.6"/>
<path d="M143.6 174.2h7.3"/>
</g>
<circle cx="46.1" cy="113.6" r="1.42" fill="#008000" stroke="#008000" stroke-width=".18"/>
<circle cx="46.1" cy="113.6" r=".8" fill="#fff" stroke="#000" stroke-width=".18"/>
<circle cx="46.1" cy="139" r="1.42" fill="#008000" stroke="#008000" stroke-width=".18"/>
<circle cx="46.1" cy="139" r=".8" fill="#fff" stroke="#000" stroke-width=".18"/>
<circle cx="36" cy="144.1" r="1.42" fill="#008000" stroke="#008000" stroke-width=".18"/>
<circle cx="36" cy="144.1" r=".8" fill="#fff" stroke="#000" stroke-width=".18"/>
<circle cx="36" cy="169.5" r="1.42" fill="#008000" stroke="#008000" stroke-width=".18"/>
<circle cx="36" cy="169.5" r=".8" fill="#fff" stroke="#000" stroke-width=".18"/>
<circle cx="36" cy="113.6" r="1.42" fill="#008000" stroke="#008000" stroke-width=".18"/>
<circle cx="36" cy="113.6" r=".8" fill="#fff" stroke="#000" stroke-width=".18"/>
<circle cx="36" cy="139" r="1.42" fill="#008000" stroke="#008000" stroke-width=".18"/>
<circle cx="36" cy="139" r=".8" fill="#fff" stroke="#000" stroke-width=".18"/>
<circle cx="46.1" cy="144.1" r="1.42" fill="#008000" stroke="#008000" stroke-width=".18"/>
<circle cx="46.1" cy="144.1" r=".8" fill="#fff" stroke="#000" stroke-width=".18"/>
<circle cx="46.1" cy="169.5" r="1.42" fill="#008000" stroke="#008000" stroke-width=".18"/>
<circle cx="46.1" cy="169.5" r=".8" fill="#fff" stroke="#000" stroke-width=".18"/>
<circle cx="117.2" cy="169.5" r="1.42" fill="#008000" stroke="#008000" stroke-width=".18"/>
<circle cx="117.2" cy="169.5" r=".8" fill="#fff" stroke="#000" stroke-width=".18"/>
<circle cx="117.2" cy="159.3" r="1.42" fill="#008000" stroke="#008000" stroke-width=".18"/>
<circle cx="117.2" cy="159.3" r=".8" fill="#fff" stroke="#000" stroke-width=".18"/>
<circle cx="74" cy="151.7" r="1.42" fill="#008000" stroke="#008000" stroke-width=".18"/>
<circle cx="74" cy="151.7" r=".8" fill="#fff" stroke="#000" stroke-width=".18"/>
<circle cx="84.2" cy="151.7" r="1.42" fill="#008000" stroke="#008000" stroke-width=".18"/>
<circle cx="84.2" cy="151.7" r=".8" fill="#fff" stroke="#000" stroke-width=".18"/>
<circle cx="117.2" cy="149.2" r="1.42" fill="#008000" stroke="#008000" stroke-width=".18"/>
<circle cx="117.2" cy="149.2" r=".8" fill="#fff" stroke="#000" stroke-width=".18"/>
<circle cx="117.2" cy="139" r="1.42" fill="#008000" stroke="#008000" stroke-width=".18"/>
<circle cx="117.2" cy="139" r=".8" fill="#fff" stroke="#000" stroke-width=".18"/>
<circle cx="109.6" cy="116.2" r="1.42" fill="#008000" stroke="#008000" stroke-width=".18"/>
<circle cx="109.6" cy="116.2" r=".8" fill="#fff" stroke="#000" stroke-width=".18"/>
<circle cx="119.8" cy="116.2" r="1.42" fill="#008000" stroke="#008000" stroke-width=".18"/>
<circle cx="119.8" cy="116.2" r=".8" fill="#fff" stroke="#000" stroke-width=".18"/>
<circle cx="99.4" cy="128.9" r="1.42" fill="#008000" stroke="#008000" stroke-width=".18"/>
<circle cx="99.4" cy="128.9" r=".8" fill="#fff" stroke="#000" stroke-width=".18"/>
<circle cx="99.4" cy="118.7" r="1.42" fill="#008000" stroke="#008000" stroke-width=".18"/>
<circle cx="99.4" cy="118.7" r=".8" fill="#fff" stroke="#000" stroke-width=".18"/>
<circle cx="109.6" cy="128.9" r="1.42" fill="#008000" stroke="#008000" stroke-width=".18"/>
<circle cx="109.6" cy="128.9" r=".8" fill="#fff" stroke="#000" stroke-width=".18"/>
<circle cx="119.8" cy="128.9" r="1.42" fill="#008000" stroke="#008000" stroke-width=".18"/>
<circle cx="119.8" cy="128.9" r=".8" fill="#fff" stroke="#000" stroke-width=".18"/>
<path d="M65.1 169.5h2.7" fill="none" stroke="#008000" stroke-width="2.6"/>
<circle cx="66.4" cy="169.5" r=".8" fill="#fff" stroke="#000" stroke-width=".18"/>
<path d="M65.1 159.3h2.7" fill="none" stroke="#008000" stroke-width="2.6"/>
<circle cx="66.4" cy="159.3" r=".8" fill="#fff" stroke="#000" stroke-width=".18"/>
<path d="M65.1 164.4h2.7" fill="none" stroke="#008000" stroke-width="2.6"/>
<circle cx="66.4" cy="164.4" r=".8" fill="#fff" stroke="#000" stroke-width=".18"/>
<circle cx="69" cy="139" r="1.67" fill="#008000" stroke="#008000" stroke-width=".18"/>
<circle cx="69" cy="139" r="1.12" fill="#fff" stroke="#000" stroke-width=".18"/>
<circle cx="89.3" cy="139" r="1.67" fill="#008000" stroke="#008000" stroke-width=".18"/>
<circle cx="89.3" cy="139" r="1.12" fill="#fff" stroke="#000" stroke-width=".18"/>
<circle cx="89.3" cy="126.3" r="1.67" fill="#008000" stroke="#008000" stroke-width=".18"/>
<circle cx="89.3" cy="126.3" r="1.12" fill="#fff" stroke="#000" stroke-width=".18"/>
<circle cx="69" cy="126.3" r="1.67" fill="#008000" stroke="#008000" stroke-width=".18"/>
<circle cx="69" cy="126.3" r="1.12" fill="#fff" stroke="#000" stroke-width=".18"/>
<circle cx="89.3" cy="85.7" r="1.67" fill="#008000" stroke="#008000" stroke-width=".18"/>
<circle cx="89.3" cy="85.7" r="1.12" fill="#fff" stroke="#000" stroke-width=".18"/>
<circle cx="69" cy="85.7" r="1.67" fill="#008000" stroke="#008000" stroke-width=".18"/>
<circle cx="69" cy="85.7" r="1.12" fill="#fff" stroke="#000" stroke-width=".18"/>
<circle cx="140.1" cy="134" r="1.42" fill="#008000" stroke="#008000" stroke-width=".18"/>
<circle cx="140.1" cy="134" r=".8" fill="#fff" stroke="#000" stroke-width=".18"/>
<circle cx="140.1" cy="159.3" r="1.42" fill="#008000" stroke="#008000" stroke-width=".18"/>
<circle cx="140.1" cy="159.3" r=".8" fill="#fff" stroke="#000" stroke-width=".18"/>
<circle cx="69" cy="113.6" r="1.67" fill="#008000" stroke="#008000" stroke-width=".18"/>
<circle cx="69" cy="113.6" r="1.12" fill="#fff" stroke="#000" stroke-width=".18"/>
<circle cx="89.3" cy="113.6" r="1.67" fill="#008000" stroke="#008000" stroke-width=".18"/>
<circle cx="89.3" cy="113.6" r="1.12" fill="#fff" stroke="#000" stroke-width=".18"/>
<path d="M82.9 164.4h2.6" fill="none" stroke="#008000" stroke-width="2.6"/>
<circle cx="84.2" cy="164.4" r=".8" fill="#fff" stroke="#000" stroke-width=".18"/>
<path d="M82.9 159.3h2.6" fill="none" stroke="#008000" stroke-width="2.6"/>
<circle cx="84.2" cy="159.3" r=".8" fill="#fff" stroke="#000" stroke-width=".18"/>
<path d="M82.9 169.5h2.6" fill="none" stroke="#008000" stroke-width="2.6"/>
<circle cx="84.2" cy="169.5" r=".8" fill="#fff" stroke="#000" stroke-width=".18"/>
<path d="M100.7 164.4h2.6" fill="none" stroke="#008000" stroke-width="2.6"/>
<circle cx="102" cy="164.4" r=".8" fill="#fff" stroke="#000" stroke-width=".18"/>
<path d="M100.7 159.3h2.6" fill="none" stroke="#008000" stroke-width="2.6"/>
<circle cx="102" cy="159.3" r=".8" fill="#fff" stroke="#000" stroke-width=".18"/>
<path d="M100.7 169.5h2.6" fill="none" stroke="#008000" stroke-width="2.6"/>
<circle cx="102" cy="169.5" r=".8" fill="#fff" stroke="#000" stroke-width=".18"/>
<path d="M105.7 103.5h2.7" fill="none" stroke="#008000" stroke-width="2.6"/>
<circle cx="107.1" cy="103.5" r=".8" fill="#fff" stroke="#000" stroke-width=".18"/>
<path d="M126 103.5h2.7" fill="none" stroke="#008000" stroke-width="2.6"/>
<circle cx="127.4" cy="103.5" r=".8" fill="#fff" stroke="#000" stroke-width=".18"/>
<path d="M67.6 100.9h2.7" fill="none" stroke="#008000" stroke-width="2.6"/>
<circle cx="69" cy="100.9" r=".8" fill="#fff" stroke="#000" stroke-width=".18"/>
<path d="M88 100.9h2.6" fill="none" stroke="#008000" stroke-width="2.6"/>
<circle cx="89.3" cy="100.9" r=".8" fill="#fff" stroke="#000" stroke-width=".18"/>
<circle cx="76.6" cy="70.5" r="1.62" fill="#008000" stroke="#008000" stroke-width=".18"/>
<circle cx="76.6" cy="70.5" r=".99" fill="#fff" stroke="#000" stroke-width=".18"/>
<circle cx="81.7" cy="70.5" r="1.62" fill="#008000" stroke="#008000" stroke-width=".18"/>
<circle cx="81.7" cy="70.5" r=".99" fill="#fff" stroke="#000" stroke-width=".18"/>
<circle cx="142.6" cy="73" r="1.62" fill="#008000" stroke="#008000" stroke-width=".18"/>
<circle cx="142.6" cy="73" r=".99" fill="#fff" stroke="#000" stroke-width=".18"/>
<circle cx="142.6" cy="78.1" r="1.62" fill="#008000" stroke="#008000" stroke-width=".18"/>
<circle cx="142.6" cy="78.1" r=".99" fill="#fff" stroke="#000" stroke-width=".18"/>
<circle cx="140.1" cy="116.2" r="1.65" fill="#008000" stroke="#008000" stroke-width=".18"/>
<circle cx="140.1" cy="116.2" r="1.1" fill="#fff" stroke="#000" stroke-width=".18"/>
<circle cx="140.1" cy="174.6" r="1.65" fill="#008000" stroke="#008000" stroke-width=".18"/>
<circle cx="140.1" cy="174.6" r="1.1" fill="#fff" stroke="#000" stroke-width=".18"/>
<g fill="none" stroke="#808080" stroke-width=".32">
<path d="M74.7 99.1l.4-.2h8.3l.2 .2 .1 .3v3.2l-.2 .3-.3 .1h-8.3l-.2-.2-.2-.3v-3.1zM75.1 83.2h8.1v5h-8.1zM77.9 85.7h4.3M79.1 84.4v2.6M79.1 85.7l2.1-1.3v2.6zM79.6 99.7h-.5v2.5M75.1 111.1h8.1v5.1h-8.1zM76.1 113.6h4.3M77.1 112.4l2 1.2-2 1.3zM77.9 100.9h4.3M79.1 112.4v2.5M79.1 100.9l2.1-1.2v2.5z"/>
<path d="M96 116.6l.4-.2h6.1l.3 .1 .2 .3v13.9l-.1 .3-.3 .1-6.2 .1-.3-.1-.2-.3v-13.9zM107.4 112.8l.4-.2h13.9l.2 .2 .1 .3v6.1l-.1 .3-.4 .2h-13.8l-.3-.2-.1-.3zM111.6 116.2h2.5M112.7 101.7l.5-.2h8.2l.3 .2 .1 .3v3.2l-.2 .2-.3 .1h-8.3l-.3-.2-.1-.3zM115.3 116.2h2.4M116 103.5h4.3M117.2 103.5l2.1-1.3v2.6zM117.7 102.2h-.5v2.6M33.8 120.2l.4-.2h3.5l.3 .1 .2 .3v.9l-.2 .2v9.7l.2 .2v.8l-.1 .3-.2 .2h-3.7l-.3-.1-.2-.3v-.9l.2-.2v-9.7l-.2-.2zM43.9 120.2l.4-.2h3.6l.3 .1 .2 .3v.9l-.2 .2v9.7l.2 .2v.8l-.1 .3-.3 .2h-3.7l-.3-.1-.1-.3-.1-.9 .3-.2v-9.7l-.3-.2zM75.1 123.8h8.1v5.1h-8.1zM75.1 136.5h8.1v5.1h-8.1z"/>
<path d="M76.1 139h4.3M77.1 137.8l2 1.2-2 1.3zM77.9 126.3h4.3M79.1 125.1v2.5M79.1 137.8v2.5M79.1 126.3l2.1-1.2v2.5zM99.4 120.8v2.3M99.4 124.4v2.5M107.4 125.5l.4-.2 14 .1 .2 .4v6.1l-.1 .3-.4 .2h-13.8l-.3-.2-.1-.3zM111.6 128.9h2.5M113.9 136.8h6.4h.3l.1 .3 .1 13.9-.2 .4-6.4 .1-.5-.2v-14zM115.3 128.9h2.4"/>
<path d="M33.8 150.7l.4-.2h3.5l.3 .1 .2 .2v.9l-.2 .3v9.6l.2 .3v.7l-.1 .3-.2 .2-3.7 .1-.3-.1-.2-.3v-.9l.2-.3v-9.6l-.2-.3zM43.9 150.7l.4-.2h3.6l.3 .1 .2 .2v.9l-.2 .3v9.6l.2 .3v.7l-.1 .3-.3 .2-3.7 .1-.3-.1-.1-.3-.1-.9 .3-.3v-9.6l-.3-.3zM71.9 148.4l.4-.2h13.8l.3 .2 .1 .3-.1 6.4-.4 .2-14-.1-.2-.4v-6.1zM76.1 151.7h2.4M79.8 151.7h2.4M113.7 157.3l.5-.2h6.1l.4 .2 .1 .3v13.7l-.2 .4-6.4 .1-.3-.1-.2-.3zM117.2 141.1v2.3M117.2 144.7v2.5M138 140.4l3.8-.1 .3 .1 .2 .3v.9l-.2 .2v9.7l.2 .2v.8v.3l-.5 .2h-3.5l-.4-.2a1.25 1.25 0 0 1 .1-1.3v-9.7l-.2-.2v-.8zM117.2 161.4v2.4M117.2 165v2.5"/>
</g>
<g fill="none" stroke="#808080" stroke-width="1.2">
<path d="M36 113.6v2.1M36 117.5v.7M46.1 113.6v2.1M46.1 117.5v.7M36 134.5v.7M36 137v2M46.1 134.5v.7M46.1 137v2M140.1 134v2M140.1 137.8v.7M36 144.1v2.1M36 147.9v.8"/>
<path d="M46.1 144.1v2.1M46.1 147.9v.8M140.1 154.8v.7M140.1 157.3v2M36 164.9v.8M36 167.5v2M46.1 164.9v.8M46.1 167.5v2"/>
</g>
<g fill="#808080" stroke="#808080" stroke-width=".18">
<path d="M45.5 132.7h1.2v1.7h-1.2z"/>
<path d="M45.5 118.3h1.2v1.7h-1.2z"/>
<path d="M45.5 135.2h1.2v1.7h-1.2z"/>
<path d="M45.5 115.7h1.2v1.8h-1.2z"/>
<path d="M35.3 163.2h1.3v1.7h-1.3z"/>
<path d="M35.3 148.7h1.3v1.8h-1.3z"/>
<path d="M35.3 165.7h1.3v1.7h-1.3z"/>
<path d="M35.3 146.2h1.3v1.7h-1.3z"/>
<path d="M35.3 132.7h1.3v1.7h-1.3z"/>
<path d="M35.3 118.3h1.3v1.7h-1.3z"/>
<path d="M35.3 135.2h1.3v1.7h-1.3z"/>
<path d="M35.3 115.7h1.3v1.8h-1.3z"/>
<path d="M45.5 163.2h1.2v1.7h-1.2z"/>
<path d="M45.5 148.7h1.2v1.8h-1.2z"/>
<path d="M45.5 165.7h1.2v1.7h-1.2z"/>
<path d="M45.5 146.2h1.2v1.7h-1.2z"/>
<path d="M81.4 136.5h1v5.1h-1z"/>
<path d="M71.2 138.3h3.9v1.5h-3.9z"/>
<path d="M83.2 138.3h3.8v1.5h-3.8z"/>
<path d="M75.8 123.8h1v5.1h-1z"/>
<path d="M83.2 125.6h3.8v1.5h-3.8z"/>
<path d="M71.2 125.6h3.9v1.5h-3.9z"/>
<path d="M75.8 83.2h1v5h-1z"/>
<path d="M83.2 84.9h3.8v1.6h-3.8z"/>
<path d="M71.2 84.9h3.9v1.6h-3.9z"/>
<path d="M139.4 153h1.3v1.7h-1.3z"/>
<path d="M139.4 138.6h1.3v1.7h-1.3z"/>
<path d="M139.4 155.5h1.3v1.8h-1.3z"/>
<path d="M139.4 136h1.3v1.8h-1.3z"/>
<path d="M81.4 111.1h1v5.1h-1z"/>
<path d="M71.2 112.9h3.9v1.5h-3.9z"/>
<path d="M83.2 112.9h3.8v1.5h-3.8z"/>
<path d="M113.4 101.5h1v4h-1z"/>
<path d="M121.8 103h3.8v1h-3.8z"/>
<path d="M108.8 103h3.8v1h-3.8z"/>
<path d="M75.3 98.9h1v4.1h-1z"/>
<path d="M83.7 100.4h3.8v1.1h-3.8z"/>
<path d="M70.7 100.4h3.8v1.1h-3.8z"/>
</g>
<path d="M114.1 114.9v2.6M115.3 114.9v2.6M98.2 124.4h2.5M98.2 123.1h2.5M114.1 127.6v2.6M115.3 127.6v2.6M78.5 150.5v2.5M79.8 150.5v2.5M116 144.7h2.5M116 143.4h2.5M116 165h2.5M116 163.8h2.5" fill="none" stroke="#808080" stroke-width=".61"/>
<g fill="none" stroke="#808080" stroke-width=".25">
<path d="M73.7 71.4h-3.1l1 1M73.7 70.4v2M87.9 70.4v2l-2-2h-.6l-.5 .5v1l.5 .5M140.7 68.1l1-1v3M140.7 70.1h2M140.7 81.8l.5-.5h1l.5 .5v.5l-2 2.1h2M66.2 159.1v10.7M83.9 159.1a5.3 5.3 0 0 1 5.6 5.3 5.3 5.3 0 0 1-5.6 5.4M83.9 159.1l-1.5 .3-1.5 .8v8.4l1.1 .7M83.9 159.1v10.7M101.7 159.1a5.3 5.3 0 0 1 5.6 5.3 5.3 5.3 0 0 1-5.6 5.4M101.7 159.1l-1.5 .3-1.5 .8v8.4l1.1 .7"/>
<path d="M101.7 159.1v10.7M64.2 169.2a5.3 5.3 0 0 0 7.5-5.4 5.3 5.3 0 0 0-8.6-3.6v8.4l1.1 .7M81.9 169.2l1 .4 1 .2M99.7 169.2l1 .4 1 .2"/>
</g>
<path d="M74.3 67.7h9.7v5.6h-9.7zM75.1 69h3v3h-3zM80.2 69h3v3h-3zM139.8 70.7h5.6v9.7h-5.6zM141.1 71.5h3v3h-3zM141.1 76.6h3v3h-3z" fill="none" stroke="#808080" stroke-width=".42"/>
<path d="M69 85.7h2M87.2 85.7h2.1M69 113.6h2M87.2 113.6h2.1M69 139h2M69 126.3h2M87.2 139h2.1M87.2 126.3h2.1" fill="none" stroke="#808080" stroke-width="1.5"/>
<path d="M69 100.9h1.7M87.5 100.9h1.8M107.1 103.5h1.7M125.6 103.5h1.8" fill="none" stroke="#808080" stroke-width="1"/>
<g fill="none" stroke="#000" stroke-width=".18">
<path d="M23.3 63.5h129.4v118.7h-129.4zM77.7 70.5h2.9M79.1 69v2.9M141.2 75.6h2.9M142.6 74.1v2.9M77.8 85.7h2.7M79.1 84.4v2.6M79.1 99.7v2.5M77.8 113.6h2.7M77.9 100.9h2.4M79.1 112.3v2.7M113.1 116.2h3.1"/>
<path d="M114.7 114.6v3.2M116 103.5h2.4M117.2 102.3v2.4M35.1 126.3h1.7M36 125.5v1.7M45.3 126.3h1.7M46.1 125.5v1.7M77.8 126.3h2.7M77.8 139h2.7M79.1 125v2.7M79.1 137.7v2.7M97.9 123.8h3.1"/>
<path d="M99.4 122.2v3.1M113.1 128.9h3.1M114.7 127.3v3.1M35.1 156.8h1.7M36 156v1.7M45.3 156.8h1.7M46.1 156v1.7M77.6 151.7h3.1M79.1 150.2v3.1M115.7 144.1h3.1M117.2 142.6v3.1M139.2 146.7h1.7"/>
<path d="M140.1 145.8v1.7M64.9 164.4h3.1M66.4 162.9v3.1M82.5 164.4h3.4M84.2 162.7v3.4M100.3 164.4h3.4M102 162.7v3.4M115.7 164.4h3.1M117.2 162.9v3.1"/>
</g>
<path d="M140.1 116.2l-10.2 53.3" fill="none" stroke="#808000" stroke-width=".18"/>
<use href="#words"/>
</svg>
